VERSION 5.7 ;
BUSBITCHARS "[]" ;
DIVIDERCHAR "/" ;

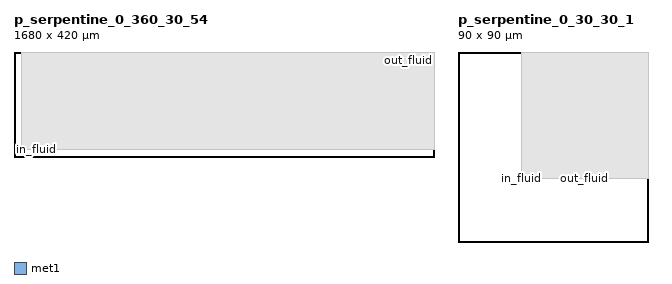
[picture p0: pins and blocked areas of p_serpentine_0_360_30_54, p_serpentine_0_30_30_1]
MACRO p_serpentine_0_360_30_54
  CLASS CORE ;
  ORIGIN  0 0 ;
  FOREIGN p_serpentine_0_360_30_54 0 0 ;
  SIZE 1680 BY 420 ;
  SYMMETRY X Y ;
  SITE CoreSite ;
  PIN in_fluid
    DIRECTION INPUT ;
    USE SIGNAL ;
    PORT
      LAYER met1 ;
        RECT 29.5 29.5 30.5 30.5 ;
    END
  END in_fluid
  PIN out_fluid
    DIRECTION OUTPUT ;
    USE SIGNAL ;
    PORT
      LAYER met1 ;
        RECT 1649.5 389.5 1650.5 390.5 ;
    END
  END out_fluid
  OBS
    LAYER met1 ;
      RECT 30 30 1680 420 ;
  END
  PROPERTY CatenaDesignType "deviceLevel" ;
END p_serpentine_0_360_30_54

MACRO p_serpentine_0_30_30_1
  CLASS CORE ;
  ORIGIN  0 0 ;
  FOREIGN p_serpentine_0_30_30_1 0 0 ;
  SIZE 90 BY 90 ;
  SYMMETRY X Y ;
  SITE CoreSite ;
  PIN in_fluid
    DIRECTION INPUT ;
    USE SIGNAL ;
    PORT
      LAYER met1 ;
        RECT 29.5 29.5 30.5 30.5 ;
    END
  END in_fluid
  PIN out_fluid
    DIRECTION OUTPUT ;
    USE SIGNAL ;
    PORT
      LAYER met1 ;
        RECT 59.5 29.5 60.5 30.5 ;
    END
  END out_fluid
  OBS
    LAYER met1 ;
      RECT 30 30 90 90 ;
  END
  PROPERTY CatenaDesignType "deviceLevel" ;
END p_serpentine_0_30_30_1

